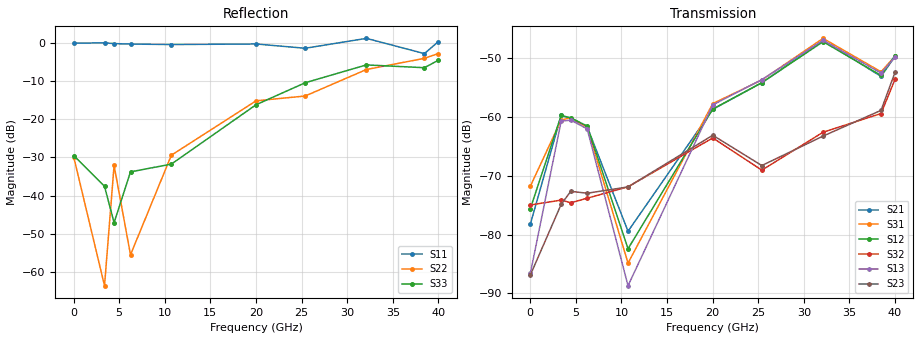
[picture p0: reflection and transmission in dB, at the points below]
! Device:  ADRF5021
! Description: SOI MMIC SPDT Non-Reflective Switch
! Frequency:  9 kHz -  30 GHz
! Ports:
! 	RFC	= Port 1
!	RF1	= Port 2
!	RF2	= Port 3
! Vdd:  +3.3 Volt
! Vss:  -2.5 Volt
! Control:  0/+3.3 Volt
! State:  All Off (Vctl= 3.3 V, Ven= 3.3 V)
! Data:	Data was collected using a calibrated network analyzer with AFR software.
!	Fixtures were calculated using AFR and fixturing was applied to collect
!	this Deembedded  S Parameter data of ADRF5021.
! Note:	Analog Devices supplies this data as a sample of measured data at the package pin
!	for this product.  Your particular data for this product may vary.
!	Data was taken at 25 degrees C.
!	Analog Devices reserves the right to change this data at anytime.
# Hz S  dB  R 50
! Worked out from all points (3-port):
!   4000 points, 10 MHz to 40 GHz, reference 50 ohm
!   strongest paths, dB at 10 MHz, 10.01 GHz, 20.01 GHz, 30.01 GHz, 40 GHz:
!     S21: -78.2, -77.3, -58.7, -52.4, -49.7
!     S31: -71.8, -82.9, -57.7, -51.8, -49.7
!     S32: -75.0, -71.8, -63.6, -65.7, -53.6
!   lowest |S11| = -2.8 dB at 38.46 GHz (marker M1), VSWR 6.23, Z = 24.1 - j68 ohm
!   |S11| at or under -10 dB: nowhere
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1e7  -0.07 -0.2  -75.58 50.3  -86.60 -165.6
     -78.21 74.6  -29.83 144.1  -86.87 9.0
     -71.78 96.8  -74.96 68.6  -29.50 144.9
3.39e9  -0.00 -33.2  -59.76 35.3  -60.71 37.3
        -59.76 36.5  -63.57 -4.5  -74.86 84.1
        -60.53 37.5  -74.14 81.2  -37.55 53.2
4.44e9  -0.19 -42.7  -60.16 25.5  -60.57 31.7
        -60.30 27.4  -32.08 -22.0  -72.65 78.1
        -60.15 33.2  -74.59 73.8  -47.07 -58.0
6.24e9  -0.31 -62.3  -61.56 10.4  -62.03 11.9
        -61.68 10.9  -55.49 -23.3  -72.97 82.7
        -61.77 13.3  -73.82 90.2  -33.77 -39.2
1.072e10  -0.44 -101.6  -82.40 -128.6  -88.68 175.4
          -79.43 -138.2  -29.41 -144.7  -71.90 91.4
          -84.84 177.4  -71.88 81.2  -31.74 -140.8
2.001e10  -0.29 177.8  -58.67 165.8  -57.96 158.9
          -58.72 165.9  -15.17 12.3  -63.12 4.7
          -57.74 157.2  -63.58 9.0  -16.19 6.1
2.539e10  -1.41 101.0  -54.19 125.6  -53.67 127.3
          -54.19 125.0  -13.91 -34.1  -68.27 -63.5
          -53.73 128.1  -69.05 -63.7  -10.44 -41.6
3.21e10  1.18 -3.4  -47.22 89.8  -46.97 75.5
         -47.02 89.5  -6.98 -42.3  -63.26 -52.9
         -46.66 74.3  -62.61 -72.2  -5.77 -70.2
3.846e10  -2.81 -68.3  -52.96 51.8  -52.56 42.8
          -53.12 53.2  -4.05 -54.1  -58.89 -150.6
          -52.34 39.6  -59.43 -149.8  -6.50 -65.5
4e10  0.34 -93.9  -49.58 55.3  -49.85 8.8
      -49.72 54.4  -2.79 -44.5  -52.40 -171.8
      -49.67 9.3  -53.58 -172.8  -4.55 -98.9
